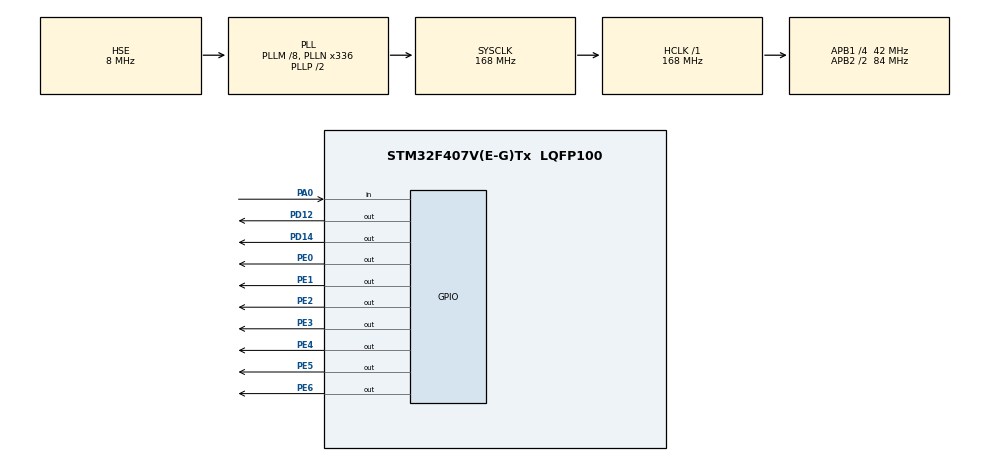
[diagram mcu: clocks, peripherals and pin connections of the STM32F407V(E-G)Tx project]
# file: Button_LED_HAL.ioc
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Mcu.Family=STM32F4
Mcu.Name=STM32F407V(E-G)Tx
Mcu.Package=LQFP100
NVIC.PriorityGroup=NVIC_PRIORITYGROUP_0
PA0-WKUP.GPIO_PuPd=GPIO_PULLDOWN
PA0-WKUP.Signal=GPIO_Input
PA13.Mode=Serial_Wire
PA13.Signal=SYS_JTMS-SWDIO
PA14.Mode=Serial_Wire
PA14.Signal=SYS_JTCK-SWCLK
PD12.GPIO_Speed=GPIO_SPEED_FREQ_VERY_HIGH
PD12.Signal=GPIO_Output
PD14.GPIO_Speed=GPIO_SPEED_FREQ_VERY_HIGH
PD14.Signal=GPIO_Output
PE0.GPIO_Speed=GPIO_SPEED_FREQ_VERY_HIGH
PE0.Signal=GPIO_Output
PE1.GPIO_Speed=GPIO_SPEED_FREQ_VERY_HIGH
PE1.Signal=GPIO_Output
PE2.GPIO_Speed=GPIO_SPEED_FREQ_VERY_HIGH
PE2.Signal=GPIO_Output
PE3.GPIO_Speed=GPIO_SPEED_FREQ_VERY_HIGH
PE3.Signal=GPIO_Output
PE4.GPIO_Speed=GPIO_SPEED_FREQ_VERY_HIGH
PE4.Signal=GPIO_Output
PE5.GPIO_Speed=GPIO_SPEED_FREQ_VERY_HIGH
PE5.Signal=GPIO_Output
PE6.GPIO_Speed=GPIO_SPEED_FREQ_VERY_HIGH
PE6.Signal=GPIO_Output
PH0-OSC_IN.Mode=HSE-External-Oscillator
PH0-OSC_IN.Signal=RCC_OSC_IN
PH1-OSC_OUT.Mode=HSE-External-Oscillator
PH1-OSC_OUT.Signal=RCC_OSC_OUT
ProjectManager.HeapSize=0x200
ProjectManager.StackSize=0x400
ProjectManager.TargetToolchain=STM32CubeIDE
RCC.48MHZClocksFreq_Value=48000000
RCC.AHBFreq_Value=168000000
RCC.APB1CLKDivider=RCC_HCLK_DIV4
RCC.APB1Freq_Value=42000000
RCC.APB1TimFreq_Value=84000000
RCC.APB2CLKDivider=RCC_HCLK_DIV2
RCC.APB2Freq_Value=84000000
RCC.APB2TimFreq_Value=168000000
RCC.CortexFreq_Value=168000000
RCC.HCLKFreq_Value=168000000
RCC.HSE_VALUE=8000000
RCC.HSI_VALUE=16000000
RCC.PLLM=8
RCC.PLLN=336
RCC.PLLQ=7
RCC.PLLSourceVirtual=RCC_PLLSOURCE_HSE
RCC.SYSCLKFreq_VALUE=168000000
RCC.SYSCLKSource=RCC_SYSCLKSOURCE_PLLCLK
RCC.VCOOutputFreq_Value=336000000
board=STM32F407G-DISC1

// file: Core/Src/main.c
#include "main.h"

int count = 0;
int number = 0;

void SystemClock_Config(void);
static void MX_GPIO_Init(void);

uint8_t segmentNumber[10] = {
        0x3f,  // 0
        0x06,  // 1
        0x5b,  // 2
        0x4f,  // 3
        0x66,  // 4
        0x6d,  // 5
        0x7d,  // 6
        0x07,  // 7
        0x7f,  // 8
        0x6f   // 9
};

void SevenSegment_Update(uint8_t number){
	HAL_GPIO_WritePin(GPIOE, GPIO_PIN_0, ((number>>0)&0x01));
	HAL_GPIO_WritePin(GPIOE, GPIO_PIN_1, ((number>>1)&0x01));
	HAL_GPIO_WritePin(GPIOE, GPIO_PIN_2, ((number>>2)&0x01));
	HAL_GPIO_WritePin(GPIOE, GPIO_PIN_3, ((number>>3)&0x01));
	HAL_GPIO_WritePin(GPIOE, GPIO_PIN_4, ((number>>4)&0x01));
	HAL_GPIO_WritePin(GPIOE, GPIO_PIN_5, ((number>>5)&0x01));
	HAL_GPIO_WritePin(GPIOE, GPIO_PIN_6, ((number>>6)&0x01));
}

int main(void)
{

  HAL_Init();

  SystemClock_Config();

  MX_GPIO_Init();

  while (1)
  {

	  if(HAL_GPIO_ReadPin(GPIOA, GPIO_PIN_0))
	  {
		  while(HAL_GPIO_ReadPin(GPIOA, GPIO_PIN_0));
		  HAL_Delay(100);

		  count++;
	  }

	  if(count % 2 == 1)
	  {
		  HAL_GPIO_WritePin(GPIOD, GPIO_PIN_12 , GPIO_PIN_SET);
		  HAL_GPIO_WritePin(GPIOD, GPIO_PIN_14 , GPIO_PIN_RESET);
		  HAL_GPIO_WritePin(GPIOE, GPIO_PIN_8 , GPIO_PIN_SET);
		  HAL_GPIO_WritePin(GPIOE, GPIO_PIN_7 , GPIO_PIN_RESET);

		  if (number == 9){
			  count++;    // Changes the mode automatically
		  }
		  else{
		  		number++;
		  }
	  }
	  else
	  {
		  HAL_GPIO_WritePin(GPIOD, GPIO_PIN_14 , GPIO_PIN_SET);
		  HAL_GPIO_WritePin(GPIOD, GPIO_PIN_12 , GPIO_PIN_RESET);
		  HAL_GPIO_WritePin(GPIOE, GPIO_PIN_7 , GPIO_PIN_SET);
		  HAL_GPIO_WritePin(GPIOE, GPIO_PIN_8 , GPIO_PIN_RESET);

		  if (number == 0){
			  count++;    // Changes the mode automatically
		  }
		  else{
		  		number--;
		  }

	  }

	  SevenSegment_Update(segmentNumber[number]);
	  HAL_Delay(1000);
  }
  /* USER CODE END 3 */
}

void SystemClock_Config(void)
{
  RCC_OscInitTypeDef RCC_OscInitStruct = {0};
  RCC_ClkInitTypeDef RCC_ClkInitStruct = {0};

  /** Configure the main internal regulator output voltage
  */
  __HAL_RCC_PWR_CLK_ENABLE();
  __HAL_PWR_VOLTAGESCALING_CONFIG(PWR_REGULATOR_VOLTAGE_SCALE1);

  /** Initializes the RCC Oscillators according to the specified parameters
  * in the RCC_OscInitTypeDef structure.
  */
  RCC_OscInitStruct.OscillatorType = RCC_OSCILLATORTYPE_HSE;
  RCC_OscInitStruct.HSEState = RCC_HSE_ON;
  RCC_OscInitStruct.PLL.PLLState = RCC_PLL_ON;
  RCC_OscInitStruct.PLL.PLLSource = RCC_PLLSOURCE_HSE;
  RCC_OscInitStruct.PLL.PLLM = 8;
  RCC_OscInitStruct.PLL.PLLN = 336;
  RCC_OscInitStruct.PLL.PLLP = RCC_PLLP_DIV2;
  RCC_OscInitStruct.PLL.PLLQ = 7;
  if (HAL_RCC_OscConfig(&RCC_OscInitStruct) != HAL_OK)
  {
    Error_Handler();
  }

  /** Initializes the CPU, AHB and APB buses clocks
  */
  RCC_ClkInitStruct.ClockType = RCC_CLOCKTYPE_HCLK|RCC_CLOCKTYPE_SYSCLK
                              |RCC_CLOCKTYPE_PCLK1|RCC_CLOCKTYPE_PCLK2;
  RCC_ClkInitStruct.SYSCLKSource = RCC_SYSCLKSOURCE_PLLCLK;
  RCC_ClkInitStruct.AHBCLKDivider = RCC_SYSCLK_DIV1;
  RCC_ClkInitStruct.APB1CLKDivider = RCC_HCLK_DIV4;
  RCC_ClkInitStruct.APB2CLKDivider = RCC_HCLK_DIV2;

  if (HAL_RCC_ClockConfig(&RCC_ClkInitStruct, FLASH_LATENCY_5) != HAL_OK)
  {
    Error_Handler();
  }
}

static void MX_GPIO_Init(void)
{
  GPIO_InitTypeDef GPIO_InitStruct = {0};

  /* GPIO Ports Clock Enable */
  __HAL_RCC_GPIOE_CLK_ENABLE();
  __HAL_RCC_GPIOH_CLK_ENABLE();
  __HAL_RCC_GPIOA_CLK_ENABLE();
  __HAL_RCC_GPIOD_CLK_ENABLE();

  /*Configure GPIO pin Output Level */
  HAL_GPIO_WritePin(GPIOE, GPIO_PIN_7 | GPIO_PIN_8  | GPIO_PIN_2|GPIO_PIN_3|GPIO_PIN_4|GPIO_PIN_5
                          |GPIO_PIN_6|GPIO_PIN_0|GPIO_PIN_1, GPIO_PIN_RESET);

  /*Configure GPIO pin Output Level */
  //HAL_GPIO_WritePin(GPIOD, GPIO_PIN_12|GPIO_PIN_14, GPIO_PIN_RESET);

  /*Configure GPIO pins : PE2 PE3 PE4 PE5
                           PE6 PE0 PE1 */
  GPIO_InitStruct.Pin = GPIO_PIN_7 | GPIO_PIN_8 |GPIO_PIN_2|GPIO_PIN_3|GPIO_PIN_4|GPIO_PIN_5
                          |GPIO_PIN_6|GPIO_PIN_0|GPIO_PIN_1;
  GPIO_InitStruct.Mode = GPIO_MODE_OUTPUT_PP;
  GPIO_InitStruct.Pull = GPIO_NOPULL;
  GPIO_InitStruct.Speed = GPIO_SPEED_FREQ_VERY_HIGH;
  HAL_GPIO_Init(GPIOE, &GPIO_InitStruct);

  /*Configure GPIO pin : PA0 */
  GPIO_InitStruct.Pin = GPIO_PIN_0;
  GPIO_InitStruct.Mode = GPIO_MODE_INPUT;
  GPIO_InitStruct.Pull = GPIO_PULLDOWN;
  HAL_GPIO_Init(GPIOA, &GPIO_InitStruct);

  /*Configure GPIO pins : PD12 PD14 */
  GPIO_InitStruct.Pin = GPIO_PIN_12|GPIO_PIN_14;
  GPIO_InitStruct.Mode = GPIO_MODE_OUTPUT_PP;
  GPIO_InitStruct.Pull = GPIO_NOPULL;
  GPIO_InitStruct.Speed = GPIO_SPEED_FREQ_VERY_HIGH;
  HAL_GPIO_Init(GPIOD, &GPIO_InitStruct);

}

void Error_Handler(void)
{
}
